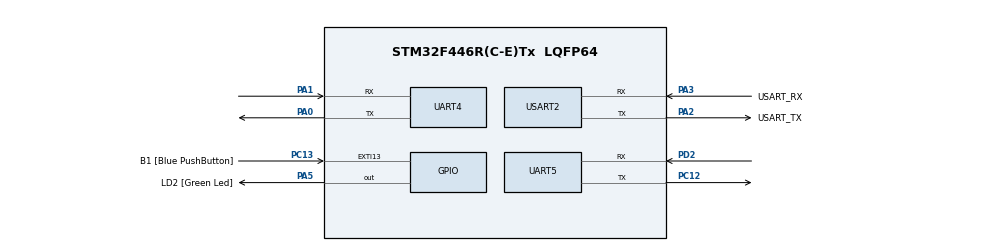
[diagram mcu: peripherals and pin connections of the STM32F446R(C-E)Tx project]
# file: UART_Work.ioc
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Mcu.Family=STM32F4
Mcu.Name=STM32F446R(C-E)Tx
Mcu.Package=LQFP64
NVIC.PriorityGroup=NVIC_PRIORITYGROUP_0
PA0-WKUP.Mode=Asynchronous
PA0-WKUP.Signal=UART4_TX
PA1.Mode=Asynchronous
PA1.Signal=UART4_RX
PA13.GPIO_Label=TMS
PA13.Signal=SYS_JTMS-SWDIO
PA14.GPIO_Label=TCK
PA14.Signal=SYS_JTCK-SWCLK
PA2.GPIO_Label=USART_TX
PA2.Mode=Asynchronous
PA2.Signal=USART2_TX
PA3.GPIO_Label=USART_RX
PA3.Mode=Asynchronous
PA3.Signal=USART2_RX
PA5.GPIO_Label=LD2 [Green Led]
PA5.Signal=GPIO_Output
PB3.GPIO_Label=SWO
PB3.Signal=SYS_JTDO-SWO
PC12.Mode=Asynchronous
PC12.Signal=UART5_TX
PC13.GPIO_Label=B1 [Blue PushButton]
PC13.GPIO_ModeDefaultEXTI=GPIO_MODE_IT_FALLING
PC13.Signal=GPXTI13
PC14-OSC32_IN.Signal=RCC_OSC32_IN
PC15-OSC32_OUT.Signal=RCC_OSC32_OUT
PD2.Mode=Asynchronous
PD2.Signal=UART5_RX
PH0-OSC_IN.Mode=HSE-External-Oscillator
PH0-OSC_IN.Signal=RCC_OSC_IN
PH1-OSC_OUT.Mode=HSE-External-Oscillator
PH1-OSC_OUT.Signal=RCC_OSC_OUT
ProjectManager.HeapSize=0x200
ProjectManager.StackSize=0x400
ProjectManager.TargetToolchain=STM32CubeIDE
RCC.AHBFreq_Value=72000000
RCC.APB1CLKDivider=RCC_HCLK_DIV2
RCC.APB1Freq_Value=36000000
RCC.APB1TimFreq_Value=72000000
RCC.APB2Freq_Value=72000000
RCC.APB2TimFreq_Value=72000000
RCC.CortexFreq_Value=72000000
RCC.FLatency-AdvancedSettings=FLASH_LATENCY_2
RCC.HCLKFreq_Value=72000000
RCC.HSE_VALUE=8000000
RCC.HSI_VALUE=16000000
RCC.LSE_VALUE=32768
RCC.PLLM=8
RCC.PLLN=72
RCC.SYSCLKFreq_VALUE=72000000
RCC.SYSCLKSource=RCC_SYSCLKSOURCE_PLLCLK
RCC.USBFreq_Value=72000000
RCC.VCOOutputFreq_Value=144000000
UART4.VirtualMode=Asynchronous
UART5.VirtualMode=Asynchronous
USART2.VirtualMode=VM_ASYNC
board=NUCLEO-F446RE

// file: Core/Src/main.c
/* USER CODE BEGIN Header */
/**
  ******************************************************************************
  * @file           : main.c
  * @brief          : Main program body
  ******************************************************************************
  * @attention
  *
  * Copyright (c) 2022 STMicroelectronics.
  * All rights reserved.
  *
  * This software is licensed under terms that can be found in the LICENSE file
  * in the root directory of this software component.
  * If no LICENSE file comes with this software, it is provided AS-IS.
  *
  ******************************************************************************
  */
/* USER CODE END Header */
#include "main.h"

/* USER CODE BEGIN Includes */
#include "stdio.h"
/* USER CODE END Includes */

UART_HandleTypeDef huart4;
UART_HandleTypeDef huart5;
UART_HandleTypeDef huart2;

void SystemClock_Config(void);
static void MX_GPIO_Init(void);
static void MX_UART4_Init(void);
static void MX_UART5_Init(void);
static void MX_USART2_UART_Init(void);

/* USER CODE BEGIN 0 */
uint8_t dataTransmit[4] = {11,22,33,44};
uint8_t dataReceive[5];

int _write (int file, char *ptr, int len)
{
	HAL_UART_Transmit(&huart2, (uint8_t*)ptr, len, 1000);
	return len;
}
/* USER CODE END 0 */

int main(void)
{

  /* MCU Configuration--------------------------------------------------------*/

  /* Reset of all peripherals, Initializes the Flash interface and the Systick. */
  HAL_Init();

  /* Configure the system clock */
  SystemClock_Config();

  /* Initialize all configured peripherals */
  MX_GPIO_Init();
  MX_UART4_Init();
  MX_UART5_Init();
  MX_USART2_UART_Init();

  /* Infinite loop */
  while (1)
  {

    /* USER CODE BEGIN 3 */
	  HAL_UART_Transmit(&huart4, dataTransmit, 4, 1000);
	  HAL_Delay(1000);
	  HAL_UART_Receive(&huart5, dataReceive, 5, 1000);
	  HAL_Delay(1000);
	  printf("\rReceived data \r\n");
	  for(int i=0; i<5; i++)
	  {
	  printf("%d\r\n", dataReceive[i]);
	  }
	  printf("\rHello all\r\n");
  }
  /* USER CODE END 3 */
}

void SystemClock_Config(void)
{
  RCC_OscInitTypeDef RCC_OscInitStruct = {0};
  RCC_ClkInitTypeDef RCC_ClkInitStruct = {0};

  /** Configure the main internal regulator output voltage
  */
  __HAL_RCC_PWR_CLK_ENABLE();
  __HAL_PWR_VOLTAGESCALING_CONFIG(PWR_REGULATOR_VOLTAGE_SCALE3);
  /** Initializes the RCC Oscillators according to the specified parameters
  * in the RCC_OscInitTypeDef structure.
  */
  RCC_OscInitStruct.OscillatorType = RCC_OSCILLATORTYPE_HSI;
  RCC_OscInitStruct.HSIState = RCC_HSI_ON;
  RCC_OscInitStruct.HSICalibrationValue = RCC_HSICALIBRATION_DEFAULT;
  RCC_OscInitStruct.PLL.PLLState = RCC_PLL_ON;
  RCC_OscInitStruct.PLL.PLLSource = RCC_PLLSOURCE_HSI;
  RCC_OscInitStruct.PLL.PLLM = 16;
  RCC_OscInitStruct.PLL.PLLN = 336;
  RCC_OscInitStruct.PLL.PLLP = RCC_PLLP_DIV4;
  RCC_OscInitStruct.PLL.PLLQ = 2;
  RCC_OscInitStruct.PLL.PLLR = 2;
  if (HAL_RCC_OscConfig(&RCC_OscInitStruct) != HAL_OK)
  {
    Error_Handler();
  }
  /** Initializes the CPU, AHB and APB buses clocks
  */
  RCC_ClkInitStruct.ClockType = RCC_CLOCKTYPE_HCLK|RCC_CLOCKTYPE_SYSCLK
                              |RCC_CLOCKTYPE_PCLK1|RCC_CLOCKTYPE_PCLK2;
  RCC_ClkInitStruct.SYSCLKSource = RCC_SYSCLKSOURCE_PLLCLK;
  RCC_ClkInitStruct.AHBCLKDivider = RCC_SYSCLK_DIV1;
  RCC_ClkInitStruct.APB1CLKDivider = RCC_HCLK_DIV2;
  RCC_ClkInitStruct.APB2CLKDivider = RCC_HCLK_DIV1;

  if (HAL_RCC_ClockConfig(&RCC_ClkInitStruct, FLASH_LATENCY_2) != HAL_OK)
  {
    Error_Handler();
  }
}

static void MX_UART4_Init(void)
{

  huart4.Instance = UART4;
  huart4.Init.BaudRate = 115200;
  huart4.Init.WordLength = UART_WORDLENGTH_8B;
  huart4.Init.StopBits = UART_STOPBITS_1;
  huart4.Init.Parity = UART_PARITY_NONE;
  huart4.Init.Mode = UART_MODE_TX_RX;
  huart4.Init.HwFlowCtl = UART_HWCONTROL_NONE;
  huart4.Init.OverSampling = UART_OVERSAMPLING_16;
  if (HAL_UART_Init(&huart4) != HAL_OK)
  {
    Error_Handler();
  }

}

static void MX_UART5_Init(void)
{

  huart5.Instance = UART5;
  huart5.Init.BaudRate = 115200;
  huart5.Init.WordLength = UART_WORDLENGTH_8B;
  huart5.Init.StopBits = UART_STOPBITS_1;
  huart5.Init.Parity = UART_PARITY_NONE;
  huart5.Init.Mode = UART_MODE_TX_RX;
  huart5.Init.HwFlowCtl = UART_HWCONTROL_NONE;
  huart5.Init.OverSampling = UART_OVERSAMPLING_16;
  if (HAL_UART_Init(&huart5) != HAL_OK)
  {
    Error_Handler();
  }

}

static void MX_USART2_UART_Init(void)
{

  huart2.Instance = USART2;
  huart2.Init.BaudRate = 115200;
  huart2.Init.WordLength = UART_WORDLENGTH_8B;
  huart2.Init.StopBits = UART_STOPBITS_1;
  huart2.Init.Parity = UART_PARITY_NONE;
  huart2.Init.Mode = UART_MODE_TX_RX;
  huart2.Init.HwFlowCtl = UART_HWCONTROL_NONE;
  huart2.Init.OverSampling = UART_OVERSAMPLING_16;
  if (HAL_UART_Init(&huart2) != HAL_OK)
  {
    Error_Handler();
  }

}

static void MX_GPIO_Init(void)
{
  GPIO_InitTypeDef GPIO_InitStruct = {0};

  /* GPIO Ports Clock Enable */
  __HAL_RCC_GPIOC_CLK_ENABLE();
  __HAL_RCC_GPIOH_CLK_ENABLE();
  __HAL_RCC_GPIOA_CLK_ENABLE();
  __HAL_RCC_GPIOD_CLK_ENABLE();
  __HAL_RCC_GPIOB_CLK_ENABLE();

  /*Configure GPIO pin Output Level */
  HAL_GPIO_WritePin(LD2_GPIO_Port, LD2_Pin, GPIO_PIN_RESET);

  /*Configure GPIO pin : B1_Pin */
  GPIO_InitStruct.Pin = B1_Pin;
  GPIO_InitStruct.Mode = GPIO_MODE_IT_FALLING;
  GPIO_InitStruct.Pull = GPIO_NOPULL;
  HAL_GPIO_Init(B1_GPIO_Port, &GPIO_InitStruct);

  /*Configure GPIO pin : LD2_Pin */
  GPIO_InitStruct.Pin = LD2_Pin;
  GPIO_InitStruct.Mode = GPIO_MODE_OUTPUT_PP;
  GPIO_InitStruct.Pull = GPIO_NOPULL;
  GPIO_InitStruct.Speed = GPIO_SPEED_FREQ_LOW;
  HAL_GPIO_Init(LD2_GPIO_Port, &GPIO_InitStruct);

}

void Error_Handler(void)
{
  __disable_irq();
  while (1)
  {
  }
}
